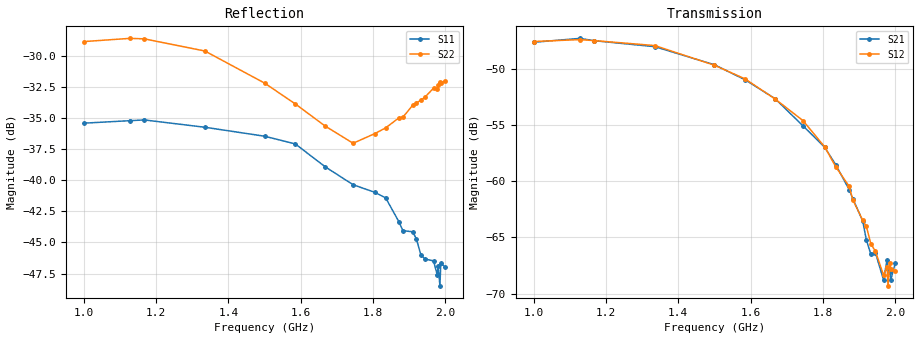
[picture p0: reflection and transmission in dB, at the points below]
!Agilent Technologies,E8363C,MY43030407,A.09.42.15
!Agilent E8363C: A.09.42.15
!Date: Friday, September 05, 2025 18:18:34
!Correction: S11(Full 2 Port(1,2))
!S21(Full 2 Port(1,2))
!S12(Full 2 Port(1,2))
!S22(Full 2 Port(1,2))
!S2P File: Measurements: S11, S21, S12, S22:
# Hz S  dB  R 50
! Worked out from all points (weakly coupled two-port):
!   401 points, 1 GHz to 2 GHz, reference 50 ohm
!   highest |S21| = -47.30 dB at 1.127 GHz (marker M1); lowest = -68.8 dB at 1.988 GHz (marker M2)
!   lowest |S11| = -48.5 dB at 1.985 GHz (marker M3), VSWR 1.01, Z = 49.7 + j0.243 ohm
!   |S11| at or under -10 dB: start of sweep to end of sweep
!   |S22| runs from -37.0 to -28.3 dB; largest |S21 - S12| = 0.00018
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1e9  -35.39 -174.6  -47.65 -56.0  -47.58 -56.6  -28.82 -154.2
1.1275e9  -35.19 173.8  -47.30 -80.4  -47.41 -80.1  -28.56 -171.4
1.1675e9  -35.13 171.6  -47.51 -87.8  -47.50 -87.5  -28.60 -177.9
1.335e9  -35.72 155.4  -48.04 -120.3  -47.94 -119.5  -29.58 154.3
1.5e9  -36.44 140.3  -49.65 -152.4  -49.69 -152.4  -32.16 124.5
1.585e9  -37.06 133.0  -50.99 -169.6  -50.91 -169.6  -33.84 103.2
1.6675e9  -38.90 135.1  -52.66 173.5  -52.69 173.5  -35.62 76.2
1.745e9  -40.35 129.2  -55.09 157.7  -54.62 155.9  -37.01 42.1
1.805e9  -40.96 124.3  -56.99 144.3  -56.96 141.7  -36.23 14.8
1.835e9  -41.41 122.5  -58.52 132.2  -58.70 132.6  -35.77 3.3
1.8725e9  -43.38 129.2  -60.75 123.5  -60.46 119.6  -34.94 -10.5
1.8825e9  -44.05 119.1  -61.55 113.4  -61.65 115.2  -34.91 -15.7
1.91e9  -44.14 125.7  -63.54 105.5  -63.49 106.3  -33.94 -21.3
1.92e9  -44.73 128.3  -65.21 93.6  -64.02 95.1  -33.74 -25.8
1.9325e9  -46.01 124.5  -66.51 93.1  -65.58 89.9  -33.55 -29.4
1.945e9  -46.35 128.9  -66.35 73.3  -66.23 76.9  -33.25 -32.7
1.9675e9  -46.48 127.9  -68.77 48.2  -68.35 61.2  -32.57 -36.8
1.9775e9  -47.60 126.0  -66.98 44.1  -67.64 42.6  -32.66 -40.6
1.98e9  -46.90 132.3  -67.78 45.0  -69.30 31.6  -32.34 -41.1
1.985e9  -48.48 139.6  -68.09 33.0  -67.24 43.9  -32.04 -42.0
1.9875e9  -46.68 129.3  -68.79 21.5  -67.78 28.9  -32.15 -41.5
2e9  -46.98 133.9  -67.30 1.9  -67.96 8.6  -31.99 -46.6
